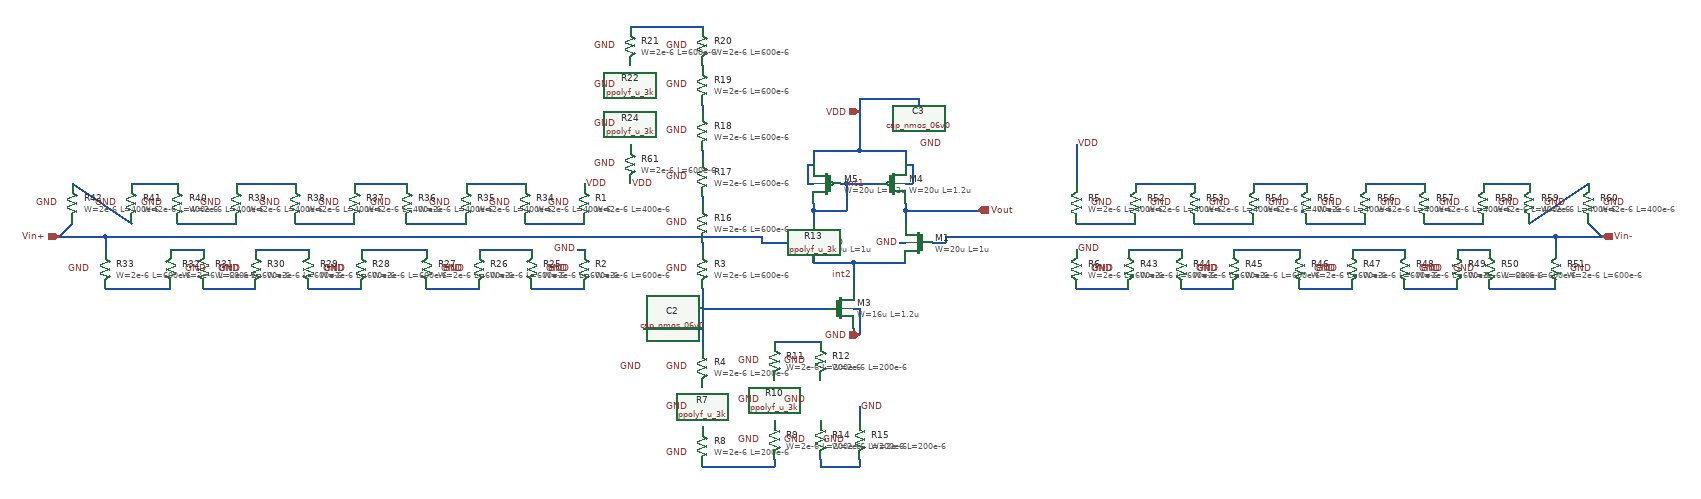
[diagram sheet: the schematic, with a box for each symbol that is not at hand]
v {xschem version=3.4.8RC file_version=1.3}
G {}
K {}
V {}
S {}
F {}
E {}
N -580 -170 -580 -160 {lab=int2}
N -520 -160 -450 -160 {lab=int2}
N -520 -160 -520 -120 {lab=int2}
N -580 -190 -570 -190 {lab=GND}
N -450 -190 -440 -190 {lab=GND}
N -520 -90 -510 -90 {lab=GND}
N -520 -60 -520 -50 {lab=GND}
N -510 -90 -510 -50 {lab=GND}
N -520 -50 -510 -50 {lab=GND}
N -450 -160 -440 -160 {lab=int2}
N -590 -280 -580 -280 {lab=VDD}
N -590 -310 -590 -280 {lab=VDD}
N -590 -310 -580 -310 {lab=VDD}
N -440 -280 -430 -280 {lab=VDD}
N -430 -310 -430 -280 {lab=VDD}
N -440 -310 -430 -310 {lab=VDD}
N -580 -240 -580 -220 {lab=int1}
N -440 -240 -440 -220 {lab=Vout}
N -580 -330 -580 -310 {lab=VDD}
N -510 -330 -440 -330 {lab=VDD}
N -440 -330 -440 -310 {lab=VDD}
N -530 -280 -480 -280 {lab=int1}
N -530 -280 -530 -240 {lab=int1}
N -580 -240 -530 -240 {lab=int1}
N -440 -240 -390 -240 {lab=Vout}
N -510 -370 -510 -330 {lab=VDD}
N -660 -190 -620 -190 {lab=Vin+}
N -570 -160 -520 -160 {lab=int2}
N -580 -160 -570 -160 {lab=int2}
N -540 -280 -530 -280 {lab=int1}
N -580 -250 -580 -240 {lab=int1}
N -440 -250 -440 -240 {lab=Vout}
N -580 -330 -510 -330 {lab=VDD}
N -390 -240 -330 -240 {lab=Vout}
N -750 -120 -750 -30 {lab=#net1}
N -840 -60 -750 -60 {lab=#net1}
N -750 -90 -560 -90 {lab=#net1}
N -510 -410 -510 -370 {lab=VDD}
N -510 -410 -420 -410 {lab=VDD}
N -420 -410 -420 -400 {lab=VDD}
N -340 -200 -190 -200 {lab=Vin-}
N -380 -200 -340 -200 {lab=Vin-}
N -380 -200 -380 -190 {lab=Vin-}
N -930 -200 -910 -200 {lab=Vin+}
N -910 -200 -870 -200 {lab=Vin+}
N -1270 -200 -1250 -200 {lab=Vin+}
N -1250 -200 -930 -200 {lab=Vin+}
N -1660 -200 -1270 -200 {lab=Vin+}
N -1660 -200 -1660 -180 {lab=Vin+}
N -1660 -120 -1560 -120 {lab=#net2}
N -1560 -180 -1510 -180 {lab=#net3}
N -1510 -120 -1430 -120 {lab=#net4}
N -1430 -180 -1350 -180 {lab=#net5}
N -1350 -120 -1270 -120 {lab=#net6}
N -1270 -180 -1170 -180 {lab=#net7}
N -1170 -120 -1090 -120 {lab=#net8}
N -1090 -180 -1010 -180 {lab=#net9}
N -1010 -120 -930 -120 {lab=#net10}
N -1020 -220 -930 -220 {lab=#net11}
N -1110 -280 -1020 -280 {lab=#net12}
N -1200 -220 -1110 -220 {lab=#net13}
N -1280 -280 -1200 -280 {lab=#net14}
N -1370 -220 -1280 -220 {lab=#net15}
N -1460 -280 -1370 -280 {lab=#net16}
N -1550 -220 -1460 -220 {lab=#net17}
N -1620 -280 -1550 -280 {lab=#net18}
N -1710 -280 -1620 -220 {lab=#net19}
N -1730 -200 -1710 -220 {lab=Vin+}
N -1730 -200 -1660 -200 {lab=Vin+}
N -940 -180 -930 -180 {lab=GND}
N -870 -200 -660 -200 {lab=Vin+}
N -660 -200 -660 -190 {lab=Vin+}
N 140 -200 160 -200 {lab=Vin-}
N -180 -200 140 -200 {lab=Vin-}
N 160 -200 550 -200 {lab=Vin-}
N 550 -200 550 -180 {lab=Vin-}
N 450 -120 550 -120 {lab=#net20}
N 400 -180 450 -180 {lab=#net21}
N 320 -120 400 -120 {lab=#net22}
N 240 -180 320 -180 {lab=#net23}
N 160 -120 240 -120 {lab=#net24}
N 60 -180 160 -180 {lab=#net25}
N -20 -120 60 -120 {lab=#net26}
N -100 -180 -20 -180 {lab=#net27}
N -180 -120 -100 -120 {lab=#net28}
N -180 -220 -90 -220 {lab=#net29}
N -90 -280 0 -280 {lab=#net30}
N 0 -220 90 -220 {lab=#net31}
N 90 -280 170 -280 {lab=#net32}
N 170 -220 260 -220 {lab=#net33}
N 260 -280 350 -280 {lab=#net34}
N 350 -220 440 -220 {lab=#net35}
N 440 -280 510 -280 {lab=#net36}
N 510 -220 600 -280 {lab=#net37}
N 600 -220 620 -200 {lab=Vin-}
N 550 -200 620 -200 {lab=Vin-}
N -180 -340 -180 -280 {lab=VDD}
N -190 -200 -180 -200 {lab=Vin-}
N -750 150 -640 150 {lab=#net38}
N -640 140 -640 150 {lab=#net38}
N -640 -40 -570 -40 {lab=#net39}
N -570 140 -570 150 {lab=#net40}
N -560 150 -510 150 {lab=#net40}
N -510 140 -510 150 {lab=#net40}
N -570 150 -560 150 {lab=#net40}
N -510 60 -510 80 {lab=GND}
N -750 -400 -750 -390 {lab=#net41}
N -750 -330 -750 -320 {lab=#net42}
N -750 -260 -750 -250 {lab=#net43}
N -860 -520 -750 -520 {lab=#net44}
N -750 -190 -750 -180 {lab=#net45}
N -400 -190 -380 -190 {lab=Vin-}
C {symbols/nfet_05v0.sym} -420 -190 0 1 {name=M1
L=1u
W=20u
nf=10
m=1
ad="'int((nf+1)/2) * W/nf * 0.18u'"
pd="'2*int((nf+1)/2) * (W/nf + 0.18u)'"
as="'int((nf+2)/2) * W/nf * 0.18u'"
ps="'2*int((nf+2)/2) * (W/nf + 0.18u)'"
nrd="'0.18u / W'" nrs="'0.18u / W'"
sa=0 sb=0 sd=0
model=nfet_05v0
spiceprefix=X
}
C {symbols/nfet_05v0.sym} -600 -190 0 0 {name=M2
L=1u
W=20u
nf=10
m=1
ad="'int((nf+1)/2) * W/nf * 0.18u'"
pd="'2*int((nf+1)/2) * (W/nf + 0.18u)'"
as="'int((nf+2)/2) * W/nf * 0.18u'"
ps="'2*int((nf+2)/2) * (W/nf + 0.18u)'"
nrd="'0.18u / W'" nrs="'0.18u / W'"
sa=0 sb=0 sd=0
model=nfet_05v0
spiceprefix=X
}
C {symbols/nfet_05v0.sym} -540 -90 0 0 {name=M3
L=1.2u
W=16u
nf=8
m=3
ad="'int((nf+1)/2) * W/nf * 0.18u'"
pd="'2*int((nf+1)/2) * (W/nf + 0.18u)'"
as="'int((nf+2)/2) * W/nf * 0.18u'"
ps="'2*int((nf+2)/2) * (W/nf + 0.18u)'"
nrd="'0.18u / W'" nrs="'0.18u / W'"
sa=0 sb=0 sd=0
model=nfet_05v0
spiceprefix=X
}
C {symbols/pfet_05v0.sym} -460 -280 0 0 {name=M4
L=1.2u
W=20u
nf=8
m=2
ad="'int((nf+1)/2) * W/nf * 0.18u'"
pd="'2*int((nf+1)/2) * (W/nf + 0.18u)'"
as="'int((nf+2)/2) * W/nf * 0.18u'"
ps="'2*int((nf+2)/2) * (W/nf + 0.18u)'"
nrd="'0.18u / W'" nrs="'0.18u / W'"
sa=0 sb=0 sd=0
model=pfet_05v0
spiceprefix=X
}
C {symbols/pfet_05v0.sym} -560 -280 0 1 {name=M5
L=1.2u
W=20u
nf=8
m=2
ad="'int((nf+1)/2) * W/nf * 0.18u'"
pd="'2*int((nf+1)/2) * (W/nf + 0.18u)'"
as="'int((nf+2)/2) * W/nf * 0.18u'"
ps="'2*int((nf+2)/2) * (W/nf + 0.18u)'"
nrd="'0.18u / W'" nrs="'0.18u / W'"
sa=0 sb=0 sd=0
model=pfet_05v0
spiceprefix=X
}
C {lab_wire.sym} -500 -280 0 0 {name=p2 sig_type=std_logic lab=int1
}
C {lab_wire.sym} -520 -140 0 0 {name=p3 sig_type=std_logic lab=int2
}
C {lab_pin.sym} -570 -190 0 1 {name=p9 sig_type=std_logic lab=GND}
C {lab_pin.sym} -450 -190 0 0 {name=p7 sig_type=std_logic lab=GND}
C {opin.sym} -330 -240 0 0 {name=p16 lab=Vout
}
C {symbols/ppolyf_u_3k.sym} -750 -150 0 0 {name=R3
W=2e-6
L=600e-6
model=ppolyf_u_3k
spiceprefix=X
m=1}
C {symbols/ppolyf_u_3k.sym} -750 0 0 0 {name=R4
W=2e-6
L=200e-6
model=ppolyf_u_3k
spiceprefix=X
m=1}
C {lab_pin.sym} -840 0 0 0 {name=p10 sig_type=std_logic lab=GND}
C {lab_pin.sym} -770 -150 0 0 {name=p11 sig_type=std_logic lab=GND}
C {lab_pin.sym} -770 0 0 0 {name=p12 sig_type=std_logic lab=GND}
C {lab_pin.sym} -860 -280 0 1 {name=p21 sig_type=std_logic lab=VDD}
C {symbols/cap_nmos_06v0.sym} -420 -370 0 0 {name=C3
W=30e-6
L=30e-6
model=cap_nmos_06v0
spiceprefix=X
m=4}
C {lab_pin.sym} -420 -340 0 1 {name=p20 sig_type=std_logic lab=GND}
C {symbols/ppolyf_u_3k.sym} -930 -250 0 0 {name=R1
W=2e-6
L=400e-6
model=ppolyf_u_3k
spiceprefix=X
m=1}
C {symbols/ppolyf_u_3k.sym} -930 -150 0 0 {name=R2
W=2e-6
L=600e-6
model=ppolyf_u_3k
spiceprefix=X
m=1}
C {lab_pin.sym} -940 -180 0 0 {name=p1 sig_type=std_logic lab=GND}
C {lab_pin.sym} -950 -250 0 0 {name=p15 sig_type=std_logic lab=GND}
C {lab_pin.sym} -950 -150 0 0 {name=p19 sig_type=std_logic lab=GND}
C {ipin.sym} -1730 -200 0 0 {name=p22 lab=Vin+}
C {symbols/ppolyf_u_3k.sym} -1010 -150 2 0 {name=R25
W=2e-6
L=600e-6
model=ppolyf_u_3k
spiceprefix=X
m=1}
C {lab_pin.sym} -990 -150 2 0 {name=p38 sig_type=std_logic lab=GND}
C {symbols/ppolyf_u_3k.sym} -1090 -150 0 0 {name=R26
W=2e-6
L=600e-6
model=ppolyf_u_3k
spiceprefix=X
m=1}
C {lab_pin.sym} -1110 -150 0 0 {name=p39 sig_type=std_logic lab=GND}
C {symbols/ppolyf_u_3k.sym} -1170 -150 2 0 {name=R27
W=2e-6
L=600e-6
model=ppolyf_u_3k
spiceprefix=X
m=1}
C {lab_pin.sym} -1150 -150 2 0 {name=p40 sig_type=std_logic lab=GND}
C {symbols/ppolyf_u_3k.sym} -1270 -150 0 0 {name=R28
W=2e-6
L=600e-6
model=ppolyf_u_3k
spiceprefix=X
m=1}
C {lab_pin.sym} -1290 -150 0 0 {name=p41 sig_type=std_logic lab=GND}
C {symbols/ppolyf_u_3k.sym} -1350 -150 2 0 {name=R29
W=2e-6
L=600e-6
model=ppolyf_u_3k
spiceprefix=X
m=1}
C {lab_pin.sym} -1330 -150 2 0 {name=p42 sig_type=std_logic lab=GND}
C {symbols/ppolyf_u_3k.sym} -1430 -150 0 0 {name=R30
W=2e-6
L=600e-6
model=ppolyf_u_3k
spiceprefix=X
m=1}
C {lab_pin.sym} -1450 -150 0 0 {name=p43 sig_type=std_logic lab=GND}
C {symbols/ppolyf_u_3k.sym} -1510 -150 2 0 {name=R31
W=2e-6
L=600e-6
model=ppolyf_u_3k
spiceprefix=X
m=1}
C {lab_pin.sym} -1490 -150 2 0 {name=p44 sig_type=std_logic lab=GND}
C {lab_pin.sym} -1540 -150 2 0 {name=p45 sig_type=std_logic lab=GND}
C {symbols/ppolyf_u_3k.sym} -1560 -150 2 0 {name=R32
W=2e-6
L=600e-6
model=ppolyf_u_3k
spiceprefix=X
m=1}
C {lab_pin.sym} -1680 -150 0 0 {name=p46 sig_type=std_logic lab=GND}
C {symbols/ppolyf_u_3k.sym} -1660 -150 0 0 {name=R33
W=2e-6
L=600e-6
model=ppolyf_u_3k
spiceprefix=X
m=1}
C {symbols/ppolyf_u_3k.sym} -1020 -250 0 0 {name=R34
W=2e-6
L=400e-6
model=ppolyf_u_3k
spiceprefix=X
m=1}
C {lab_pin.sym} -1040 -250 0 0 {name=p47 sig_type=std_logic lab=GND}
C {symbols/ppolyf_u_3k.sym} -1110 -250 0 0 {name=R35
W=2e-6
L=400e-6
model=ppolyf_u_3k
spiceprefix=X
m=1}
C {lab_pin.sym} -1130 -250 0 0 {name=p48 sig_type=std_logic lab=GND}
C {symbols/ppolyf_u_3k.sym} -1200 -250 0 0 {name=R36
W=2e-6
L=400e-6
model=ppolyf_u_3k
spiceprefix=X
m=1}
C {lab_pin.sym} -1220 -250 0 0 {name=p49 sig_type=std_logic lab=GND}
C {symbols/ppolyf_u_3k.sym} -1280 -250 0 0 {name=R37
W=2e-6
L=400e-6
model=ppolyf_u_3k
spiceprefix=X
m=1}
C {lab_pin.sym} -1300 -250 0 0 {name=p50 sig_type=std_logic lab=GND}
C {symbols/ppolyf_u_3k.sym} -1370 -250 0 0 {name=R38
W=2e-6
L=400e-6
model=ppolyf_u_3k
spiceprefix=X
m=1}
C {lab_pin.sym} -1390 -250 0 0 {name=p51 sig_type=std_logic lab=GND}
C {symbols/ppolyf_u_3k.sym} -1460 -250 0 0 {name=R39
W=2e-6
L=400e-6
model=ppolyf_u_3k
spiceprefix=X
m=1}
C {lab_pin.sym} -1480 -250 0 0 {name=p52 sig_type=std_logic lab=GND}
C {symbols/ppolyf_u_3k.sym} -1550 -250 0 0 {name=R40
W=2e-6
L=400e-6
model=ppolyf_u_3k
spiceprefix=X
m=1}
C {lab_pin.sym} -1570 -250 0 0 {name=p53 sig_type=std_logic lab=GND}
C {symbols/ppolyf_u_3k.sym} -1620 -250 0 0 {name=R41
W=2e-6
L=400e-6
model=ppolyf_u_3k
spiceprefix=X
m=1}
C {lab_pin.sym} -1640 -250 0 0 {name=p54 sig_type=std_logic lab=GND}
C {symbols/ppolyf_u_3k.sym} -1710 -250 0 0 {name=R42
W=2e-6
L=400e-6
model=ppolyf_u_3k
spiceprefix=X
m=1}
C {lab_pin.sym} -1730 -250 0 0 {name=p55 sig_type=std_logic lab=GND}
C {lab_pin.sym} -930 -280 0 1 {name=p23 sig_type=std_logic lab=VDD}
C {ipin.sym} 620 -200 0 1 {name=p13 lab=Vin-}
C {symbols/ppolyf_u_3k.sym} -180 -250 0 1 {name=R5
W=2e-6
L=400e-6
model=ppolyf_u_3k
spiceprefix=X
m=1}
C {symbols/ppolyf_u_3k.sym} -180 -150 0 1 {name=R6
W=2e-6
L=600e-6
model=ppolyf_u_3k
spiceprefix=X
m=1}
C {lab_pin.sym} -180 -180 0 1 {name=p14 sig_type=std_logic lab=GND}
C {lab_pin.sym} -160 -250 0 1 {name=p17 sig_type=std_logic lab=GND}
C {lab_pin.sym} -160 -150 0 1 {name=p18 sig_type=std_logic lab=GND}
C {symbols/ppolyf_u_3k.sym} -100 -150 2 1 {name=R43
W=2e-6
L=600e-6
model=ppolyf_u_3k
spiceprefix=X
m=1}
C {lab_pin.sym} -120 -150 2 1 {name=p56 sig_type=std_logic lab=GND}
C {symbols/ppolyf_u_3k.sym} -20 -150 0 1 {name=R44
W=2e-6
L=600e-6
model=ppolyf_u_3k
spiceprefix=X
m=1}
C {lab_pin.sym} 0 -150 0 1 {name=p57 sig_type=std_logic lab=GND}
C {symbols/ppolyf_u_3k.sym} 60 -150 2 1 {name=R45
W=2e-6
L=600e-6
model=ppolyf_u_3k
spiceprefix=X
m=1}
C {lab_pin.sym} 40 -150 2 1 {name=p58 sig_type=std_logic lab=GND}
C {symbols/ppolyf_u_3k.sym} 160 -150 0 1 {name=R46
W=2e-6
L=600e-6
model=ppolyf_u_3k
spiceprefix=X
m=1}
C {lab_pin.sym} 180 -150 0 1 {name=p59 sig_type=std_logic lab=GND}
C {symbols/ppolyf_u_3k.sym} 240 -150 2 1 {name=R47
W=2e-6
L=600e-6
model=ppolyf_u_3k
spiceprefix=X
m=1}
C {lab_pin.sym} 220 -150 2 1 {name=p60 sig_type=std_logic lab=GND}
C {symbols/ppolyf_u_3k.sym} 320 -150 0 1 {name=R48
W=2e-6
L=600e-6
model=ppolyf_u_3k
spiceprefix=X
m=1}
C {lab_pin.sym} 340 -150 0 1 {name=p61 sig_type=std_logic lab=GND}
C {symbols/ppolyf_u_3k.sym} 400 -150 2 1 {name=R49
W=2e-6
L=600e-6
model=ppolyf_u_3k
spiceprefix=X
m=1}
C {lab_pin.sym} 380 -150 2 1 {name=p62 sig_type=std_logic lab=GND}
C {lab_pin.sym} 430 -150 2 1 {name=p63 sig_type=std_logic lab=GND}
C {symbols/ppolyf_u_3k.sym} 450 -150 2 1 {name=R50
W=2e-6
L=600e-6
model=ppolyf_u_3k
spiceprefix=X
m=1}
C {lab_pin.sym} 570 -150 0 1 {name=p64 sig_type=std_logic lab=GND}
C {symbols/ppolyf_u_3k.sym} 550 -150 0 1 {name=R51
W=2e-6
L=600e-6
model=ppolyf_u_3k
spiceprefix=X
m=1}
C {symbols/ppolyf_u_3k.sym} -90 -250 0 1 {name=R52
W=2e-6
L=400e-6
model=ppolyf_u_3k
spiceprefix=X
m=1}
C {lab_pin.sym} -70 -250 0 1 {name=p65 sig_type=std_logic lab=GND}
C {symbols/ppolyf_u_3k.sym} 0 -250 0 1 {name=R53
W=2e-6
L=400e-6
model=ppolyf_u_3k
spiceprefix=X
m=1}
C {lab_pin.sym} 20 -250 0 1 {name=p66 sig_type=std_logic lab=GND}
C {symbols/ppolyf_u_3k.sym} 90 -250 0 1 {name=R54
W=2e-6
L=400e-6
model=ppolyf_u_3k
spiceprefix=X
m=1}
C {lab_pin.sym} 110 -250 0 1 {name=p67 sig_type=std_logic lab=GND}
C {symbols/ppolyf_u_3k.sym} 170 -250 0 1 {name=R55
W=2e-6
L=400e-6
model=ppolyf_u_3k
spiceprefix=X
m=1}
C {lab_pin.sym} 190 -250 0 1 {name=p68 sig_type=std_logic lab=GND}
C {symbols/ppolyf_u_3k.sym} 260 -250 0 1 {name=R56
W=2e-6
L=400e-6
model=ppolyf_u_3k
spiceprefix=X
m=1}
C {lab_pin.sym} 280 -250 0 1 {name=p69 sig_type=std_logic lab=GND}
C {symbols/ppolyf_u_3k.sym} 350 -250 0 1 {name=R57
W=2e-6
L=400e-6
model=ppolyf_u_3k
spiceprefix=X
m=1}
C {lab_pin.sym} 370 -250 0 1 {name=p70 sig_type=std_logic lab=GND}
C {symbols/ppolyf_u_3k.sym} 440 -250 0 1 {name=R58
W=2e-6
L=400e-6
model=ppolyf_u_3k
spiceprefix=X
m=1}
C {lab_pin.sym} 460 -250 0 1 {name=p71 sig_type=std_logic lab=GND}
C {symbols/ppolyf_u_3k.sym} 510 -250 0 1 {name=R59
W=2e-6
L=400e-6
model=ppolyf_u_3k
spiceprefix=X
m=1}
C {lab_pin.sym} 530 -250 0 1 {name=p72 sig_type=std_logic lab=GND}
C {symbols/ppolyf_u_3k.sym} 600 -250 0 1 {name=R60
W=2e-6
L=400e-6
model=ppolyf_u_3k
spiceprefix=X
m=1}
C {lab_pin.sym} 620 -250 0 1 {name=p73 sig_type=std_logic lab=GND}
C {symbols/ppolyf_u_3k.sym} -750 60 0 0 {name=R7
W=2e-6
L=200e-6
model=ppolyf_u_3k
spiceprefix=X
m=1}
C {lab_pin.sym} -770 60 0 0 {name=p8 sig_type=std_logic lab=GND}
C {symbols/ppolyf_u_3k.sym} -750 120 0 0 {name=R8
W=2e-6
L=200e-6
model=ppolyf_u_3k
spiceprefix=X
m=1}
C {lab_pin.sym} -770 130 0 0 {name=p25 sig_type=std_logic lab=GND}
C {symbols/ppolyf_u_3k.sym} -640 110 0 0 {name=R9
W=2e-6
L=200e-6
model=ppolyf_u_3k
spiceprefix=X
m=1}
C {lab_pin.sym} -660 110 0 0 {name=p26 sig_type=std_logic lab=GND}
C {symbols/ppolyf_u_3k.sym} -640 50 0 0 {name=R10
W=2e-6
L=200e-6
model=ppolyf_u_3k
spiceprefix=X
m=1}
C {lab_pin.sym} -660 50 0 0 {name=p27 sig_type=std_logic lab=GND}
C {symbols/ppolyf_u_3k.sym} -640 -10 0 0 {name=R11
W=2e-6
L=200e-6
model=ppolyf_u_3k
spiceprefix=X
m=1}
C {lab_pin.sym} -660 -10 0 0 {name=p28 sig_type=std_logic lab=GND}
C {symbols/ppolyf_u_3k.sym} -570 -10 0 0 {name=R12
W=2e-6
L=200e-6
model=ppolyf_u_3k
spiceprefix=X
m=1}
C {lab_pin.sym} -590 -10 0 0 {name=p29 sig_type=std_logic lab=GND}
C {symbols/ppolyf_u_3k.sym} -570 50 0 0 {name=R13
W=2e-6
L=200e-6
model=ppolyf_u_3k
spiceprefix=X
m=1}
C {lab_pin.sym} -590 50 0 0 {name=p30 sig_type=std_logic lab=GND}
C {symbols/ppolyf_u_3k.sym} -570 110 0 0 {name=R14
W=2e-6
L=200e-6
model=ppolyf_u_3k
spiceprefix=X
m=1}
C {lab_pin.sym} -590 110 0 0 {name=p31 sig_type=std_logic lab=GND}
C {symbols/ppolyf_u_3k.sym} -510 110 0 0 {name=R15
W=2e-6
L=200e-6
model=ppolyf_u_3k
spiceprefix=X
m=1}
C {lab_pin.sym} -530 110 0 0 {name=p32 sig_type=std_logic lab=GND}
C {lab_pin.sym} -510 60 0 1 {name=p33 sig_type=std_logic lab=GND}
C {symbols/ppolyf_u_3k.sym} -750 -220 0 0 {name=R16
W=2e-6
L=600e-6
model=ppolyf_u_3k
spiceprefix=X
m=1}
C {symbols/ppolyf_u_3k.sym} -750 -290 0 0 {name=R17
W=2e-6
L=600e-6
model=ppolyf_u_3k
spiceprefix=X
m=1}
C {symbols/ppolyf_u_3k.sym} -750 -360 0 0 {name=R18
W=2e-6
L=600e-6
model=ppolyf_u_3k
spiceprefix=X
m=1}
C {symbols/ppolyf_u_3k.sym} -750 -430 0 0 {name=R19
W=2e-6
L=600e-6
model=ppolyf_u_3k
spiceprefix=X
m=1}
C {symbols/ppolyf_u_3k.sym} -750 -490 0 0 {name=R20
W=2e-6
L=600e-6
model=ppolyf_u_3k
spiceprefix=X
m=1}
C {symbols/ppolyf_u_3k.sym} -860 -490 0 0 {name=R21
W=2e-6
L=600e-6
model=ppolyf_u_3k
spiceprefix=X
m=1}
C {symbols/ppolyf_u_3k.sym} -860 -430 0 0 {name=R22
W=2e-6
L=600e-6
model=ppolyf_u_3k
spiceprefix=X
m=1}
C {symbols/ppolyf_u_3k.sym} -860 -370 0 0 {name=R24
W=2e-6
L=600e-6
model=ppolyf_u_3k
spiceprefix=X
m=1}
C {symbols/ppolyf_u_3k.sym} -860 -310 0 0 {name=R61
W=2e-6
L=600e-6
model=ppolyf_u_3k
spiceprefix=X
m=1}
C {lab_pin.sym} -770 -220 0 0 {name=p34 sig_type=std_logic lab=GND}
C {lab_pin.sym} -770 -290 0 0 {name=p35 sig_type=std_logic lab=GND}
C {lab_pin.sym} -770 -360 0 0 {name=p36 sig_type=std_logic lab=GND}
C {lab_pin.sym} -770 -430 0 0 {name=p37 sig_type=std_logic lab=GND}
C {lab_pin.sym} -770 -490 0 0 {name=p74 sig_type=std_logic lab=GND}
C {lab_pin.sym} -880 -490 0 0 {name=p75 sig_type=std_logic lab=GND}
C {lab_pin.sym} -880 -430 0 0 {name=p76 sig_type=std_logic lab=GND}
C {lab_pin.sym} -880 -370 0 0 {name=p77 sig_type=std_logic lab=GND}
C {lab_pin.sym} -880 -310 0 0 {name=p78 sig_type=std_logic lab=GND}
C {iopin.sym} -510 -390 0 0 {name=p4 lab=VDD}
C {iopin.sym} -510 -50 0 0 {name=p5 lab=GND}
C {lab_pin.sym} -180 -340 0 1 {name=p6 sig_type=std_logic lab=VDD}
C {symbols/cap_nmos_06v0.sym} -840 -30 0 0 {name=C2
W=30e-6
L=30e-6
model=cap_nmos_06v0
spiceprefix=X
m=4}
